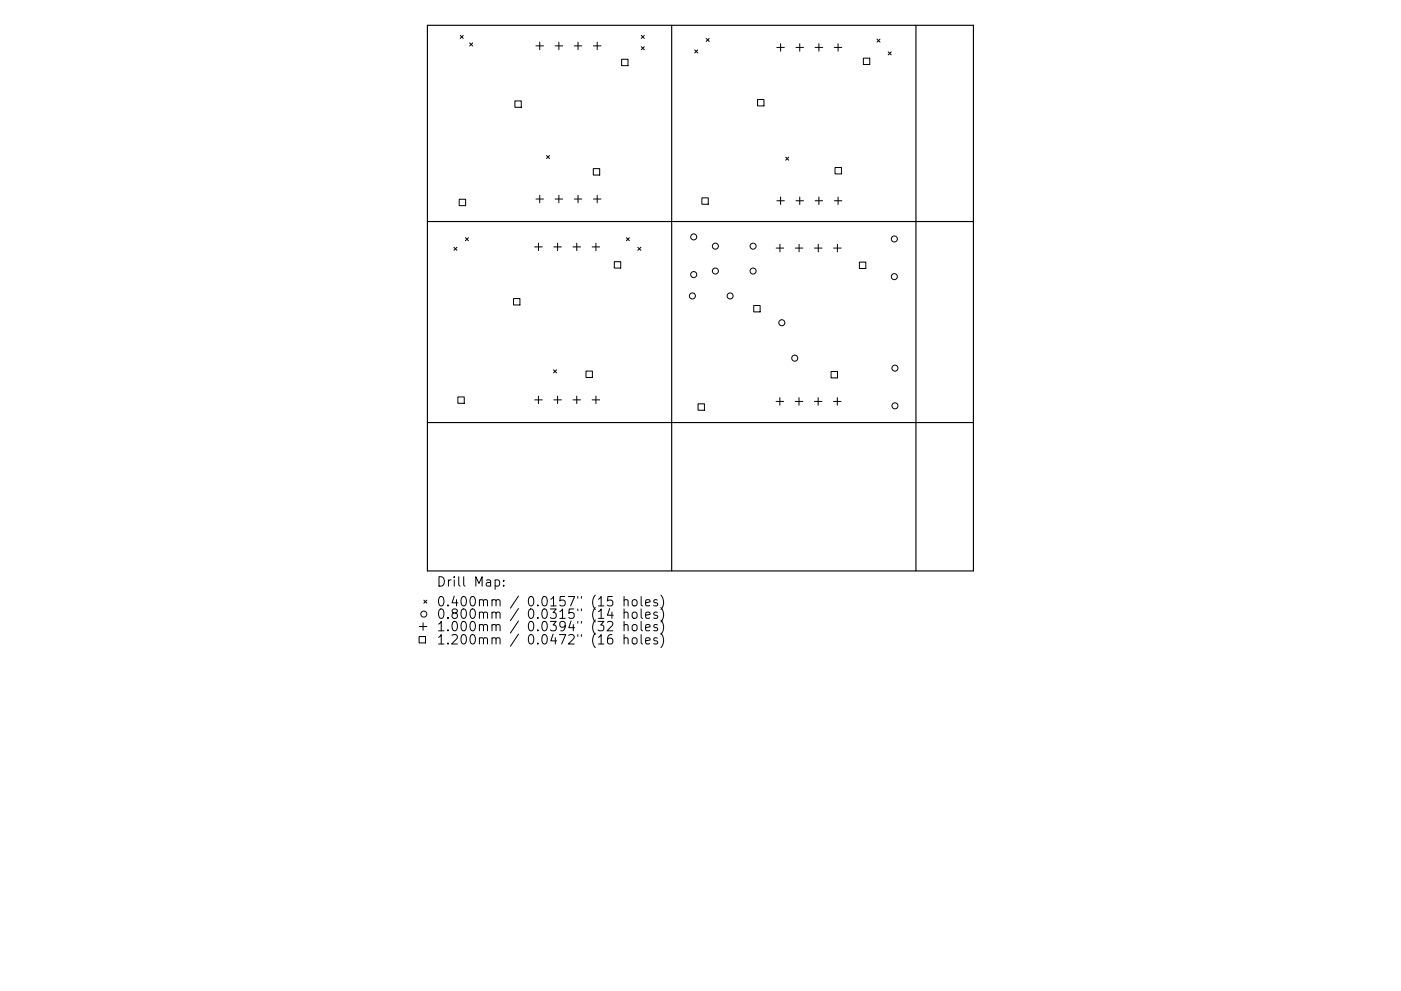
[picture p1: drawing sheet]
<svg xmlns="http://www.w3.org/2000/svg" width="297mm" height="210mm" viewBox="0 0 297 210" stroke-linecap="round" stroke-linejoin="round" font-family="sans-serif">
<defs><g id="words">
<g font-size="2.8">
<text x="92.5" y="125.1">Drill</text>
<text x="100.5" y="125.1">Map:</text>
<text x="92.5" y="129.3">0.400mm</text>
<text x="92.5" y="131.9">0.800mm</text>
<text x="111.9" y="129.3">0.0157&quot;</text>
<text x="111.9" y="131.9">0.0315&quot;</text>
<text x="125.7" y="129.3">(15</text>
<text x="125.7" y="131.9">(14</text>
<text x="132.5" y="129.3">holes)</text>
<text x="132.5" y="131.9">holes)</text>
<text x="92.5" y="134.5">1.000mm</text>
<text x="92.5" y="137.3">1.200mm</text>
<text x="111.9" y="134.5">0.0394&quot;</text>
<text x="111.9" y="137.3">0.0472&quot;</text>
<text x="125.7" y="134.5">(32</text>
<text x="125.7" y="137.3">(16</text>
<text x="132.5" y="134.5">holes)</text>
<text x="132.5" y="137.3">holes)</text>
</g>
</g></defs>
<path d="M90.6 5.4h115.8v115.7h-115.8zM142.4 5.4v115.7M194.2 5.4v115.7M90.6 47h115.8M90.6 89.7h115.8" fill="none" stroke="#000" stroke-width=".24"/>
<g fill="none" stroke="#000" stroke-width=".21">
<path d="M97.6 7.5l.6 .7M98.2 7.5l-.6 .7M99.6 9.1l.6 .6M100.2 9.1l-.6 .6M113.6 9.7h1.6M114.4 8.9v1.6M117.7 9.7h1.6M118.5 8.9v1.6M121.8 9.7h1.6M122.6 8.9v1.6M125.8 9.7h1.6M126.6 8.9v1.6"/>
<path d="M131.8 12.6h1.4v1.3h-1.4zM136 7.5l.6 .7M136 9.9l.6 .6M136.6 7.5l-.6 .7M136.6 9.9l-.6 .6M147.3 10.6l.6 .6M147.9 10.6l-.6 .6M149.7 8.2l.7 .6M150.4 8.2l-.7 .6M164.7 10.1h1.6M165.5 9.3v1.6M168.8 10.1h1.6"/>
<path d="M169.6 9.3v1.6M172.8 10.1h1.6M173.6 9.3v1.6M176.9 10.1h1.6M177.7 9.3v1.6M183 12.3h1.4v1.4h-1.4zM185.9 8.3l.7 .6M186.6 8.3l-.7 .6M188.3 11l.7 .6M189 11l-.7 .6M109.2 21.4h1.3v1.4h-1.3zM115.9 33l.6 .6"/>
<path d="M116.5 33l-.6 .6M125.8 35.8h1.3v1.3h-1.3zM160.6 21.1h1.4v1.4h-1.4zM166.6 33.3l.6 .7M167.2 33.3l-.6 .7M177 35.5h1.4v1.4h-1.4zM96.2 52.5l.7 .6M96.9 52.5l-.7 .6M97.4 42.3h1.3v1.3h-1.3zM98.7 50.4l.6 .7M99.3 50.4l-.6 .7M113.4 52.4h1.6"/>
<path d="M113.6 42.2h1.6M114.2 51.6v1.6M114.4 41.4v1.6M117.4 52.4h1.6M117.7 42.2h1.6M118.2 51.6v1.6M118.5 41.4v1.6M121.5 52.4h1.6M121.8 42.2h1.6M122.3 51.6v1.6M122.6 41.4v1.6M125.5 52.4h1.6"/>
<path d="M125.8 42.2h1.6M126.3 51.6v1.6M126.6 41.4v1.6M130.2 55.5h1.4v1.4h-1.4zM132.8 50.4l.6 .7M133.4 50.4l-.6 .7M135.2 52.5l.7 .6M135.9 52.5l-.7 .6M148.8 42h1.4v1.3h-1.4zM164.6 52.6h1.6M164.7 42.6h1.6M165.4 51.8v1.6"/>
<path d="M165.5 41.8v1.6M168.6 52.6h1.6M168.8 42.6h1.6M169.4 51.8v1.6M169.6 41.8v1.6M172.7 52.6h1.6M172.8 42.6h1.6M173.5 51.8v1.6M173.6 41.8v1.6M176.7 52.6h1.6M176.9 42.6h1.6M177.5 51.8v1.6"/>
<path d="M177.7 41.8v1.6M182.2 55.6h1.4v1.4h-1.4zM108.9 63.3h1.3v1.4h-1.3zM117.4 78.5l.6 .6M118 78.5l-.6 .6M124.2 78.7h1.4v1.4h-1.4zM159.8 64.8h1.4v1.4h-1.4zM176.2 78.8h1.4v1.4h-1.4zM97.1 84.2h1.3v1.4h-1.3zM113.4 84.8h1.6M114.2 84v1.6M117.4 84.8h1.6"/>
<path d="M118.2 84v1.6M121.5 84.8h1.6M122.3 84v1.6M125.5 84.8h1.6M126.3 84v1.6M148 85.7h1.4v1.3h-1.4zM164.5 85.2h1.6M165.3 84.4v1.6M168.6 85.2h1.6M169.4 84.4v1.6M172.7 85.2h1.6M173.5 84.4v1.6"/>
<path d="M176.7 85.2h1.6M177.5 84.4v1.6M88.9 135.1h1.3v1.3h-1.3zM88.9 132.9h1.6M89.7 132.1v1.6M89.9 127.3l.6 .7M90.5 127.3l-.6 .7M98.3 122.4v1.7l.3 .3M104.3 127.4l.3-.2 .5 .1 .1 1.3M104.3 130.1a.5 .5 0 0 1 .9 0v1.1M104.3 132.7a.5 .5 0 0 1 .9 .1v1M104.3 135.5a.5 .5 0 0 1 .9 .1v1"/>
<path d="M105.2 127.5l.3-.3 .4 .1 .1 1.3M105.2 130.1l.3-.2 .4 .1 .1 1.2M105.2 132.8l.3-.3 .4 .1 .1 1.2M105.2 135.6l.3-.3 .4 .1 .1 1.2M109.9 126.5l-1.7 2.5M109.9 129.1l-1.7 2.6M109.9 131.7l-1.7 2.6M109.9 134.5l-1.7 2.6M122.5 126.6v.3M122.5 129.2v.4M122.5 131.8v.4M122.5 134.6v.4"/>
<path d="M123.3 126.6v.3M123.3 129.2v.4M123.3 131.8v.4M123.3 134.6v.4"/>
<circle cx="147.1" cy="58.3" r=".64"/>
<circle cx="147.1" cy="50.3" r=".64"/>
<circle cx="151.7" cy="57.5" r=".64"/>
<circle cx="151.7" cy="52.2" r=".64"/>
<circle cx="159.7" cy="57.5" r=".64"/>
<circle cx="159.7" cy="52.2" r=".64"/>
<circle cx="189.6" cy="58.7" r=".64"/>
<circle cx="189.6" cy="50.7" r=".64"/>
<circle cx="146.8" cy="62.8" r=".64"/>
<circle cx="154.8" cy="62.8" r=".64"/>
<circle cx="165.8" cy="68.5" r=".64"/>
<circle cx="168.5" cy="76" r=".64"/>
<circle cx="189.7" cy="78.1" r=".64"/>
<circle cx="189.7" cy="86.1" r=".64"/>
<circle cx="89.9" cy="130.3" r=".64"/>
</g>
<use href="#words"/>
</svg>
